VERSION 5.7 ;
BUSBITCHARS "[]" ;
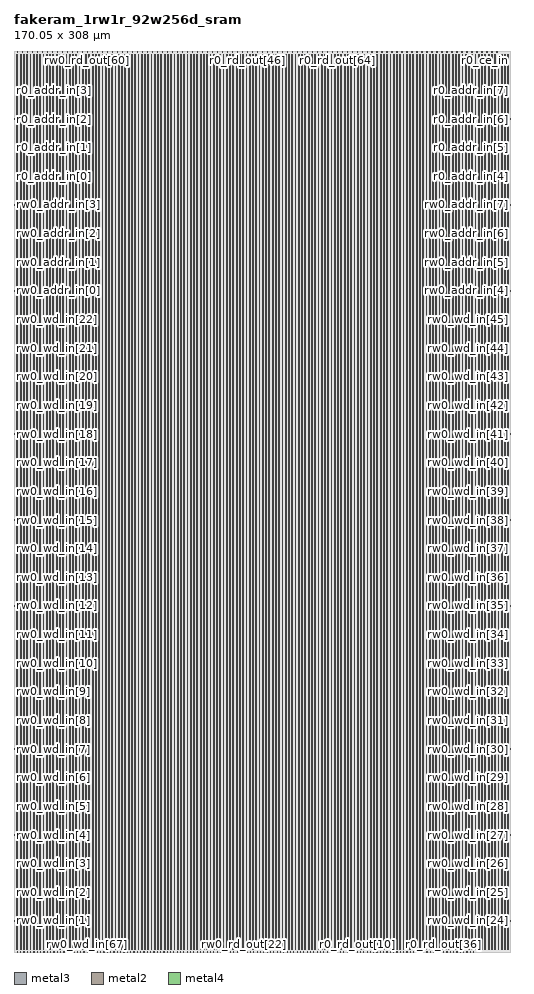
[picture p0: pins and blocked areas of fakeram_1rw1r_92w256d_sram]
MACRO fakeram_1rw1r_92w256d_sram
  FOREIGN fakeram_1rw1r_92w256d_sram 0 0 ;
  SYMMETRY X Y R90 ;
  SIZE 170.050 BY 308.000 ;
  CLASS BLOCK ;
  PIN rw0_wd_in[0]
    DIRECTION INPUT ;
    USE SIGNAL ;
    SHAPE ABUTMENT ;
    PORT
      LAYER metal3 ;
      RECT 0.000 0.805 0.210 0.875 ;
    END
  END rw0_wd_in[0]
  PIN rw0_wd_in[1]
    DIRECTION INPUT ;
    USE SIGNAL ;
    SHAPE ABUTMENT ;
    PORT
      LAYER metal3 ;
      RECT 0.000 10.605 0.210 10.675 ;
    END
  END rw0_wd_in[1]
  PIN rw0_wd_in[2]
    DIRECTION INPUT ;
    USE SIGNAL ;
    SHAPE ABUTMENT ;
    PORT
      LAYER metal3 ;
      RECT 0.000 20.405 0.210 20.475 ;
    END
  END rw0_wd_in[2]
  PIN rw0_wd_in[3]
    DIRECTION INPUT ;
    USE SIGNAL ;
    SHAPE ABUTMENT ;
    PORT
      LAYER metal3 ;
      RECT 0.000 30.205 0.210 30.275 ;
    END
  END rw0_wd_in[3]
  PIN rw0_wd_in[4]
    DIRECTION INPUT ;
    USE SIGNAL ;
    SHAPE ABUTMENT ;
    PORT
      LAYER metal3 ;
      RECT 0.000 40.005 0.210 40.075 ;
    END
  END rw0_wd_in[4]
  PIN rw0_wd_in[5]
    DIRECTION INPUT ;
    USE SIGNAL ;
    SHAPE ABUTMENT ;
    PORT
      LAYER metal3 ;
      RECT 0.000 49.805 0.210 49.875 ;
    END
  END rw0_wd_in[5]
  PIN rw0_wd_in[6]
    DIRECTION INPUT ;
    USE SIGNAL ;
    SHAPE ABUTMENT ;
    PORT
      LAYER metal3 ;
      RECT 0.000 59.605 0.210 59.675 ;
    END
  END rw0_wd_in[6]
  PIN rw0_wd_in[7]
    DIRECTION INPUT ;
    USE SIGNAL ;
    SHAPE ABUTMENT ;
    PORT
      LAYER metal3 ;
      RECT 0.000 69.405 0.210 69.475 ;
    END
  END rw0_wd_in[7]
  PIN rw0_wd_in[8]
    DIRECTION INPUT ;
    USE SIGNAL ;
    SHAPE ABUTMENT ;
    PORT
      LAYER metal3 ;
      RECT 0.000 79.205 0.210 79.275 ;
    END
  END rw0_wd_in[8]
  PIN rw0_wd_in[9]
    DIRECTION INPUT ;
    USE SIGNAL ;
    SHAPE ABUTMENT ;
    PORT
      LAYER metal3 ;
      RECT 0.000 89.005 0.210 89.075 ;
    END
  END rw0_wd_in[9]
  PIN rw0_wd_in[10]
    DIRECTION INPUT ;
    USE SIGNAL ;
    SHAPE ABUTMENT ;
    PORT
      LAYER metal3 ;
      RECT 0.000 98.805 0.210 98.875 ;
    END
  END rw0_wd_in[10]
  PIN rw0_wd_in[11]
    DIRECTION INPUT ;
    USE SIGNAL ;
    SHAPE ABUTMENT ;
    PORT
      LAYER metal3 ;
      RECT 0.000 108.605 0.210 108.675 ;
    END
  END rw0_wd_in[11]
  PIN rw0_wd_in[12]
    DIRECTION INPUT ;
    USE SIGNAL ;
    SHAPE ABUTMENT ;
    PORT
      LAYER metal3 ;
      RECT 0.000 118.405 0.210 118.475 ;
    END
  END rw0_wd_in[12]
  PIN rw0_wd_in[13]
    DIRECTION INPUT ;
    USE SIGNAL ;
    SHAPE ABUTMENT ;
    PORT
      LAYER metal3 ;
      RECT 0.000 128.205 0.210 128.275 ;
    END
  END rw0_wd_in[13]
  PIN rw0_wd_in[14]
    DIRECTION INPUT ;
    USE SIGNAL ;
    SHAPE ABUTMENT ;
    PORT
      LAYER metal3 ;
      RECT 0.000 138.005 0.210 138.075 ;
    END
  END rw0_wd_in[14]
  PIN rw0_wd_in[15]
    DIRECTION INPUT ;
    USE SIGNAL ;
    SHAPE ABUTMENT ;
    PORT
      LAYER metal3 ;
      RECT 0.000 147.805 0.210 147.875 ;
    END
  END rw0_wd_in[15]
  PIN rw0_wd_in[16]
    DIRECTION INPUT ;
    USE SIGNAL ;
    SHAPE ABUTMENT ;
    PORT
      LAYER metal3 ;
      RECT 0.000 157.605 0.210 157.675 ;
    END
  END rw0_wd_in[16]
  PIN rw0_wd_in[17]
    DIRECTION INPUT ;
    USE SIGNAL ;
    SHAPE ABUTMENT ;
    PORT
      LAYER metal3 ;
      RECT 0.000 167.405 0.210 167.475 ;
    END
  END rw0_wd_in[17]
  PIN rw0_wd_in[18]
    DIRECTION INPUT ;
    USE SIGNAL ;
    SHAPE ABUTMENT ;
    PORT
      LAYER metal3 ;
      RECT 0.000 177.205 0.210 177.275 ;
    END
  END rw0_wd_in[18]
  PIN rw0_wd_in[19]
    DIRECTION INPUT ;
    USE SIGNAL ;
    SHAPE ABUTMENT ;
    PORT
      LAYER metal3 ;
      RECT 0.000 187.005 0.210 187.075 ;
    END
  END rw0_wd_in[19]
  PIN rw0_wd_in[20]
    DIRECTION INPUT ;
    USE SIGNAL ;
    SHAPE ABUTMENT ;
    PORT
      LAYER metal3 ;
      RECT 0.000 196.805 0.210 196.875 ;
    END
  END rw0_wd_in[20]
  PIN rw0_wd_in[21]
    DIRECTION INPUT ;
    USE SIGNAL ;
    SHAPE ABUTMENT ;
    PORT
      LAYER metal3 ;
      RECT 0.000 206.605 0.210 206.675 ;
    END
  END rw0_wd_in[21]
  PIN rw0_wd_in[22]
    DIRECTION INPUT ;
    USE SIGNAL ;
    SHAPE ABUTMENT ;
    PORT
      LAYER metal3 ;
      RECT 0.000 216.405 0.210 216.475 ;
    END
  END rw0_wd_in[22]
  PIN rw0_wd_in[23]
    DIRECTION INPUT ;
    USE SIGNAL ;
    SHAPE ABUTMENT ;
    PORT
      LAYER metal3 ;
      RECT 169.840 0.805 170.050 0.875 ;
    END
  END rw0_wd_in[23]
  PIN rw0_wd_in[24]
    DIRECTION INPUT ;
    USE SIGNAL ;
    SHAPE ABUTMENT ;
    PORT
      LAYER metal3 ;
      RECT 169.840 10.605 170.050 10.675 ;
    END
  END rw0_wd_in[24]
  PIN rw0_wd_in[25]
    DIRECTION INPUT ;
    USE SIGNAL ;
    SHAPE ABUTMENT ;
    PORT
      LAYER metal3 ;
      RECT 169.840 20.405 170.050 20.475 ;
    END
  END rw0_wd_in[25]
  PIN rw0_wd_in[26]
    DIRECTION INPUT ;
    USE SIGNAL ;
    SHAPE ABUTMENT ;
    PORT
      LAYER metal3 ;
      RECT 169.840 30.205 170.050 30.275 ;
    END
  END rw0_wd_in[26]
  PIN rw0_wd_in[27]
    DIRECTION INPUT ;
    USE SIGNAL ;
    SHAPE ABUTMENT ;
    PORT
      LAYER metal3 ;
      RECT 169.840 40.005 170.050 40.075 ;
    END
  END rw0_wd_in[27]
  PIN rw0_wd_in[28]
    DIRECTION INPUT ;
    USE SIGNAL ;
    SHAPE ABUTMENT ;
    PORT
      LAYER metal3 ;
      RECT 169.840 49.805 170.050 49.875 ;
    END
  END rw0_wd_in[28]
  PIN rw0_wd_in[29]
    DIRECTION INPUT ;
    USE SIGNAL ;
    SHAPE ABUTMENT ;
    PORT
      LAYER metal3 ;
      RECT 169.840 59.605 170.050 59.675 ;
    END
  END rw0_wd_in[29]
  PIN rw0_wd_in[30]
    DIRECTION INPUT ;
    USE SIGNAL ;
    SHAPE ABUTMENT ;
    PORT
      LAYER metal3 ;
      RECT 169.840 69.405 170.050 69.475 ;
    END
  END rw0_wd_in[30]
  PIN rw0_wd_in[31]
    DIRECTION INPUT ;
    USE SIGNAL ;
    SHAPE ABUTMENT ;
    PORT
      LAYER metal3 ;
      RECT 169.840 79.205 170.050 79.275 ;
    END
  END rw0_wd_in[31]
  PIN rw0_wd_in[32]
    DIRECTION INPUT ;
    USE SIGNAL ;
    SHAPE ABUTMENT ;
    PORT
      LAYER metal3 ;
      RECT 169.840 89.005 170.050 89.075 ;
    END
  END rw0_wd_in[32]
  PIN rw0_wd_in[33]
    DIRECTION INPUT ;
    USE SIGNAL ;
    SHAPE ABUTMENT ;
    PORT
      LAYER metal3 ;
      RECT 169.840 98.805 170.050 98.875 ;
    END
  END rw0_wd_in[33]
  PIN rw0_wd_in[34]
    DIRECTION INPUT ;
    USE SIGNAL ;
    SHAPE ABUTMENT ;
    PORT
      LAYER metal3 ;
      RECT 169.840 108.605 170.050 108.675 ;
    END
  END rw0_wd_in[34]
  PIN rw0_wd_in[35]
    DIRECTION INPUT ;
    USE SIGNAL ;
    SHAPE ABUTMENT ;
    PORT
      LAYER metal3 ;
      RECT 169.840 118.405 170.050 118.475 ;
    END
  END rw0_wd_in[35]
  PIN rw0_wd_in[36]
    DIRECTION INPUT ;
    USE SIGNAL ;
    SHAPE ABUTMENT ;
    PORT
      LAYER metal3 ;
      RECT 169.840 128.205 170.050 128.275 ;
    END
  END rw0_wd_in[36]
  PIN rw0_wd_in[37]
    DIRECTION INPUT ;
    USE SIGNAL ;
    SHAPE ABUTMENT ;
    PORT
      LAYER metal3 ;
      RECT 169.840 138.005 170.050 138.075 ;
    END
  END rw0_wd_in[37]
  PIN rw0_wd_in[38]
    DIRECTION INPUT ;
    USE SIGNAL ;
    SHAPE ABUTMENT ;
    PORT
      LAYER metal3 ;
      RECT 169.840 147.805 170.050 147.875 ;
    END
  END rw0_wd_in[38]
  PIN rw0_wd_in[39]
    DIRECTION INPUT ;
    USE SIGNAL ;
    SHAPE ABUTMENT ;
    PORT
      LAYER metal3 ;
      RECT 169.840 157.605 170.050 157.675 ;
    END
  END rw0_wd_in[39]
  PIN rw0_wd_in[40]
    DIRECTION INPUT ;
    USE SIGNAL ;
    SHAPE ABUTMENT ;
    PORT
      LAYER metal3 ;
      RECT 169.840 167.405 170.050 167.475 ;
    END
  END rw0_wd_in[40]
  PIN rw0_wd_in[41]
    DIRECTION INPUT ;
    USE SIGNAL ;
    SHAPE ABUTMENT ;
    PORT
      LAYER metal3 ;
      RECT 169.840 177.205 170.050 177.275 ;
    END
  END rw0_wd_in[41]
  PIN rw0_wd_in[42]
    DIRECTION INPUT ;
    USE SIGNAL ;
    SHAPE ABUTMENT ;
    PORT
      LAYER metal3 ;
      RECT 169.840 187.005 170.050 187.075 ;
    END
  END rw0_wd_in[42]
  PIN rw0_wd_in[43]
    DIRECTION INPUT ;
    USE SIGNAL ;
    SHAPE ABUTMENT ;
    PORT
      LAYER metal3 ;
      RECT 169.840 196.805 170.050 196.875 ;
    END
  END rw0_wd_in[43]
  PIN rw0_wd_in[44]
    DIRECTION INPUT ;
    USE SIGNAL ;
    SHAPE ABUTMENT ;
    PORT
      LAYER metal3 ;
      RECT 169.840 206.605 170.050 206.675 ;
    END
  END rw0_wd_in[44]
  PIN rw0_wd_in[45]
    DIRECTION INPUT ;
    USE SIGNAL ;
    SHAPE ABUTMENT ;
    PORT
      LAYER metal3 ;
      RECT 169.840 216.405 170.050 216.475 ;
    END
  END rw0_wd_in[45]
  PIN rw0_wd_in[46]
    DIRECTION INPUT ;
    USE SIGNAL ;
    SHAPE ABUTMENT ;
    PORT
      LAYER metal2 ;
      RECT 1.105 0.000 1.175 0.210 ;
    END
  END rw0_wd_in[46]
  PIN rw0_wd_in[47]
    DIRECTION INPUT ;
    USE SIGNAL ;
    SHAPE ABUTMENT ;
    PORT
      LAYER metal2 ;
      RECT 2.245 0.000 2.315 0.210 ;
    END
  END rw0_wd_in[47]
  PIN rw0_wd_in[48]
    DIRECTION INPUT ;
    USE SIGNAL ;
    SHAPE ABUTMENT ;
    PORT
      LAYER metal2 ;
      RECT 3.385 0.000 3.455 0.210 ;
    END
  END rw0_wd_in[48]
  PIN rw0_wd_in[49]
    DIRECTION INPUT ;
    USE SIGNAL ;
    SHAPE ABUTMENT ;
    PORT
      LAYER metal2 ;
      RECT 4.525 0.000 4.595 0.210 ;
    END
  END rw0_wd_in[49]
  PIN rw0_wd_in[50]
    DIRECTION INPUT ;
    USE SIGNAL ;
    SHAPE ABUTMENT ;
    PORT
      LAYER metal2 ;
      RECT 5.665 0.000 5.735 0.210 ;
    END
  END rw0_wd_in[50]
  PIN rw0_wd_in[51]
    DIRECTION INPUT ;
    USE SIGNAL ;
    SHAPE ABUTMENT ;
    PORT
      LAYER metal2 ;
      RECT 6.805 0.000 6.875 0.210 ;
    END
  END rw0_wd_in[51]
  PIN rw0_wd_in[52]
    DIRECTION INPUT ;
    USE SIGNAL ;
    SHAPE ABUTMENT ;
    PORT
      LAYER metal2 ;
      RECT 7.945 0.000 8.015 0.210 ;
    END
  END rw0_wd_in[52]
  PIN rw0_wd_in[53]
    DIRECTION INPUT ;
    USE SIGNAL ;
    SHAPE ABUTMENT ;
    PORT
      LAYER metal2 ;
      RECT 9.085 0.000 9.155 0.210 ;
    END
  END rw0_wd_in[53]
  PIN rw0_wd_in[54]
    DIRECTION INPUT ;
    USE SIGNAL ;
    SHAPE ABUTMENT ;
    PORT
      LAYER metal2 ;
      RECT 10.225 0.000 10.295 0.210 ;
    END
  END rw0_wd_in[54]
  PIN rw0_wd_in[55]
    DIRECTION INPUT ;
    USE SIGNAL ;
    SHAPE ABUTMENT ;
    PORT
      LAYER metal2 ;
      RECT 11.365 0.000 11.435 0.210 ;
    END
  END rw0_wd_in[55]
  PIN rw0_wd_in[56]
    DIRECTION INPUT ;
    USE SIGNAL ;
    SHAPE ABUTMENT ;
    PORT
      LAYER metal2 ;
      RECT 12.505 0.000 12.575 0.210 ;
    END
  END rw0_wd_in[56]
  PIN rw0_wd_in[57]
    DIRECTION INPUT ;
    USE SIGNAL ;
    SHAPE ABUTMENT ;
    PORT
      LAYER metal2 ;
      RECT 13.645 0.000 13.715 0.210 ;
    END
  END rw0_wd_in[57]
  PIN rw0_wd_in[58]
    DIRECTION INPUT ;
    USE SIGNAL ;
    SHAPE ABUTMENT ;
    PORT
      LAYER metal2 ;
      RECT 14.785 0.000 14.855 0.210 ;
    END
  END rw0_wd_in[58]
  PIN rw0_wd_in[59]
    DIRECTION INPUT ;
    USE SIGNAL ;
    SHAPE ABUTMENT ;
    PORT
      LAYER metal2 ;
      RECT 15.925 0.000 15.995 0.210 ;
    END
  END rw0_wd_in[59]
  PIN rw0_wd_in[60]
    DIRECTION INPUT ;
    USE SIGNAL ;
    SHAPE ABUTMENT ;
    PORT
      LAYER metal2 ;
      RECT 17.065 0.000 17.135 0.210 ;
    END
  END rw0_wd_in[60]
  PIN rw0_wd_in[61]
    DIRECTION INPUT ;
    USE SIGNAL ;
    SHAPE ABUTMENT ;
    PORT
      LAYER metal2 ;
      RECT 18.205 0.000 18.275 0.210 ;
    END
  END rw0_wd_in[61]
  PIN rw0_wd_in[62]
    DIRECTION INPUT ;
    USE SIGNAL ;
    SHAPE ABUTMENT ;
    PORT
      LAYER metal2 ;
      RECT 19.345 0.000 19.415 0.210 ;
    END
  END rw0_wd_in[62]
  PIN rw0_wd_in[63]
    DIRECTION INPUT ;
    USE SIGNAL ;
    SHAPE ABUTMENT ;
    PORT
      LAYER metal2 ;
      RECT 20.485 0.000 20.555 0.210 ;
    END
  END rw0_wd_in[63]
  PIN rw0_wd_in[64]
    DIRECTION INPUT ;
    USE SIGNAL ;
    SHAPE ABUTMENT ;
    PORT
      LAYER metal2 ;
      RECT 21.625 0.000 21.695 0.210 ;
    END
  END rw0_wd_in[64]
  PIN rw0_wd_in[65]
    DIRECTION INPUT ;
    USE SIGNAL ;
    SHAPE ABUTMENT ;
    PORT
      LAYER metal2 ;
      RECT 22.765 0.000 22.835 0.210 ;
    END
  END rw0_wd_in[65]
  PIN rw0_wd_in[66]
    DIRECTION INPUT ;
    USE SIGNAL ;
    SHAPE ABUTMENT ;
    PORT
      LAYER metal2 ;
      RECT 23.905 0.000 23.975 0.210 ;
    END
  END rw0_wd_in[66]
  PIN rw0_wd_in[67]
    DIRECTION INPUT ;
    USE SIGNAL ;
    SHAPE ABUTMENT ;
    PORT
      LAYER metal2 ;
      RECT 25.045 0.000 25.115 0.210 ;
    END
  END rw0_wd_in[67]
  PIN rw0_wd_in[68]
    DIRECTION INPUT ;
    USE SIGNAL ;
    SHAPE ABUTMENT ;
    PORT
      LAYER metal2 ;
      RECT 26.185 0.000 26.255 0.210 ;
    END
  END rw0_wd_in[68]
  PIN rw0_wd_in[69]
    DIRECTION INPUT ;
    USE SIGNAL ;
    SHAPE ABUTMENT ;
    PORT
      LAYER metal2 ;
      RECT 27.325 0.000 27.395 0.210 ;
    END
  END rw0_wd_in[69]
  PIN rw0_wd_in[70]
    DIRECTION INPUT ;
    USE SIGNAL ;
    SHAPE ABUTMENT ;
    PORT
      LAYER metal2 ;
      RECT 28.465 0.000 28.535 0.210 ;
    END
  END rw0_wd_in[70]
  PIN rw0_wd_in[71]
    DIRECTION INPUT ;
    USE SIGNAL ;
    SHAPE ABUTMENT ;
    PORT
      LAYER metal2 ;
      RECT 29.605 0.000 29.675 0.210 ;
    END
  END rw0_wd_in[71]
  PIN rw0_wd_in[72]
    DIRECTION INPUT ;
    USE SIGNAL ;
    SHAPE ABUTMENT ;
    PORT
      LAYER metal2 ;
      RECT 30.745 0.000 30.815 0.210 ;
    END
  END rw0_wd_in[72]
  PIN rw0_wd_in[73]
    DIRECTION INPUT ;
    USE SIGNAL ;
    SHAPE ABUTMENT ;
    PORT
      LAYER metal2 ;
      RECT 31.885 0.000 31.955 0.210 ;
    END
  END rw0_wd_in[73]
  PIN rw0_wd_in[74]
    DIRECTION INPUT ;
    USE SIGNAL ;
    SHAPE ABUTMENT ;
    PORT
      LAYER metal2 ;
      RECT 33.025 0.000 33.095 0.210 ;
    END
  END rw0_wd_in[74]
  PIN rw0_wd_in[75]
    DIRECTION INPUT ;
    USE SIGNAL ;
    SHAPE ABUTMENT ;
    PORT
      LAYER metal2 ;
      RECT 34.165 0.000 34.235 0.210 ;
    END
  END rw0_wd_in[75]
  PIN rw0_wd_in[76]
    DIRECTION INPUT ;
    USE SIGNAL ;
    SHAPE ABUTMENT ;
    PORT
      LAYER metal2 ;
      RECT 35.305 0.000 35.375 0.210 ;
    END
  END rw0_wd_in[76]
  PIN rw0_wd_in[77]
    DIRECTION INPUT ;
    USE SIGNAL ;
    SHAPE ABUTMENT ;
    PORT
      LAYER metal2 ;
      RECT 36.445 0.000 36.515 0.210 ;
    END
  END rw0_wd_in[77]
  PIN rw0_wd_in[78]
    DIRECTION INPUT ;
    USE SIGNAL ;
    SHAPE ABUTMENT ;
    PORT
      LAYER metal2 ;
      RECT 37.585 0.000 37.655 0.210 ;
    END
  END rw0_wd_in[78]
  PIN rw0_wd_in[79]
    DIRECTION INPUT ;
    USE SIGNAL ;
    SHAPE ABUTMENT ;
    PORT
      LAYER metal2 ;
      RECT 38.725 0.000 38.795 0.210 ;
    END
  END rw0_wd_in[79]
  PIN rw0_wd_in[80]
    DIRECTION INPUT ;
    USE SIGNAL ;
    SHAPE ABUTMENT ;
    PORT
      LAYER metal2 ;
      RECT 39.865 0.000 39.935 0.210 ;
    END
  END rw0_wd_in[80]
  PIN rw0_wd_in[81]
    DIRECTION INPUT ;
    USE SIGNAL ;
    SHAPE ABUTMENT ;
    PORT
      LAYER metal2 ;
      RECT 41.005 0.000 41.075 0.210 ;
    END
  END rw0_wd_in[81]
  PIN rw0_wd_in[82]
    DIRECTION INPUT ;
    USE SIGNAL ;
    SHAPE ABUTMENT ;
    PORT
      LAYER metal2 ;
      RECT 42.145 0.000 42.215 0.210 ;
    END
  END rw0_wd_in[82]
  PIN rw0_wd_in[83]
    DIRECTION INPUT ;
    USE SIGNAL ;
    SHAPE ABUTMENT ;
    PORT
      LAYER metal2 ;
      RECT 43.285 0.000 43.355 0.210 ;
    END
  END rw0_wd_in[83]
  PIN rw0_wd_in[84]
    DIRECTION INPUT ;
    USE SIGNAL ;
    SHAPE ABUTMENT ;
    PORT
      LAYER metal2 ;
      RECT 44.425 0.000 44.495 0.210 ;
    END
  END rw0_wd_in[84]
  PIN rw0_wd_in[85]
    DIRECTION INPUT ;
    USE SIGNAL ;
    SHAPE ABUTMENT ;
    PORT
      LAYER metal2 ;
      RECT 45.565 0.000 45.635 0.210 ;
    END
  END rw0_wd_in[85]
  PIN rw0_wd_in[86]
    DIRECTION INPUT ;
    USE SIGNAL ;
    SHAPE ABUTMENT ;
    PORT
      LAYER metal2 ;
      RECT 46.705 0.000 46.775 0.210 ;
    END
  END rw0_wd_in[86]
  PIN rw0_wd_in[87]
    DIRECTION INPUT ;
    USE SIGNAL ;
    SHAPE ABUTMENT ;
    PORT
      LAYER metal2 ;
      RECT 47.845 0.000 47.915 0.210 ;
    END
  END rw0_wd_in[87]
  PIN rw0_wd_in[88]
    DIRECTION INPUT ;
    USE SIGNAL ;
    SHAPE ABUTMENT ;
    PORT
      LAYER metal2 ;
      RECT 48.985 0.000 49.055 0.210 ;
    END
  END rw0_wd_in[88]
  PIN rw0_wd_in[89]
    DIRECTION INPUT ;
    USE SIGNAL ;
    SHAPE ABUTMENT ;
    PORT
      LAYER metal2 ;
      RECT 50.125 0.000 50.195 0.210 ;
    END
  END rw0_wd_in[89]
  PIN rw0_wd_in[90]
    DIRECTION INPUT ;
    USE SIGNAL ;
    SHAPE ABUTMENT ;
    PORT
      LAYER metal2 ;
      RECT 51.265 0.000 51.335 0.210 ;
    END
  END rw0_wd_in[90]
  PIN rw0_wd_in[91]
    DIRECTION INPUT ;
    USE SIGNAL ;
    SHAPE ABUTMENT ;
    PORT
      LAYER metal2 ;
      RECT 52.405 0.000 52.475 0.210 ;
    END
  END rw0_wd_in[91]
  PIN rw0_rd_out[0]
    DIRECTION OUTPUT ;
    USE SIGNAL ;
    SHAPE ABUTMENT ;
    PORT
      LAYER metal2 ;
      RECT 53.545 0.000 53.615 0.210 ;
    END
  END rw0_rd_out[0]
  PIN rw0_rd_out[1]
    DIRECTION OUTPUT ;
    USE SIGNAL ;
    SHAPE ABUTMENT ;
    PORT
      LAYER metal2 ;
      RECT 54.685 0.000 54.755 0.210 ;
    END
  END rw0_rd_out[1]
  PIN rw0_rd_out[2]
    DIRECTION OUTPUT ;
    USE SIGNAL ;
    SHAPE ABUTMENT ;
    PORT
      LAYER metal2 ;
      RECT 55.825 0.000 55.895 0.210 ;
    END
  END rw0_rd_out[2]
  PIN rw0_rd_out[3]
    DIRECTION OUTPUT ;
    USE SIGNAL ;
    SHAPE ABUTMENT ;
    PORT
      LAYER metal2 ;
      RECT 56.965 0.000 57.035 0.210 ;
    END
  END rw0_rd_out[3]
  PIN rw0_rd_out[4]
    DIRECTION OUTPUT ;
    USE SIGNAL ;
    SHAPE ABUTMENT ;
    PORT
      LAYER metal2 ;
      RECT 58.105 0.000 58.175 0.210 ;
    END
  END rw0_rd_out[4]
  PIN rw0_rd_out[5]
    DIRECTION OUTPUT ;
    USE SIGNAL ;
    SHAPE ABUTMENT ;
    PORT
      LAYER metal2 ;
      RECT 59.245 0.000 59.315 0.210 ;
    END
  END rw0_rd_out[5]
  PIN rw0_rd_out[6]
    DIRECTION OUTPUT ;
    USE SIGNAL ;
    SHAPE ABUTMENT ;
    PORT
      LAYER metal2 ;
      RECT 60.385 0.000 60.455 0.210 ;
    END
  END rw0_rd_out[6]
  PIN rw0_rd_out[7]
    DIRECTION OUTPUT ;
    USE SIGNAL ;
    SHAPE ABUTMENT ;
    PORT
      LAYER metal2 ;
      RECT 61.525 0.000 61.595 0.210 ;
    END
  END rw0_rd_out[7]
  PIN rw0_rd_out[8]
    DIRECTION OUTPUT ;
    USE SIGNAL ;
    SHAPE ABUTMENT ;
    PORT
      LAYER metal2 ;
      RECT 62.665 0.000 62.735 0.210 ;
    END
  END rw0_rd_out[8]
  PIN rw0_rd_out[9]
    DIRECTION OUTPUT ;
    USE SIGNAL ;
    SHAPE ABUTMENT ;
    PORT
      LAYER metal2 ;
      RECT 63.805 0.000 63.875 0.210 ;
    END
  END rw0_rd_out[9]
  PIN rw0_rd_out[10]
    DIRECTION OUTPUT ;
    USE SIGNAL ;
    SHAPE ABUTMENT ;
    PORT
      LAYER metal2 ;
      RECT 64.945 0.000 65.015 0.210 ;
    END
  END rw0_rd_out[10]
  PIN rw0_rd_out[11]
    DIRECTION OUTPUT ;
    USE SIGNAL ;
    SHAPE ABUTMENT ;
    PORT
      LAYER metal2 ;
      RECT 66.085 0.000 66.155 0.210 ;
    END
  END rw0_rd_out[11]
  PIN rw0_rd_out[12]
    DIRECTION OUTPUT ;
    USE SIGNAL ;
    SHAPE ABUTMENT ;
    PORT
      LAYER metal2 ;
      RECT 67.225 0.000 67.295 0.210 ;
    END
  END rw0_rd_out[12]
  PIN rw0_rd_out[13]
    DIRECTION OUTPUT ;
    USE SIGNAL ;
    SHAPE ABUTMENT ;
    PORT
      LAYER metal2 ;
      RECT 68.365 0.000 68.435 0.210 ;
    END
  END rw0_rd_out[13]
  PIN rw0_rd_out[14]
    DIRECTION OUTPUT ;
    USE SIGNAL ;
    SHAPE ABUTMENT ;
    PORT
      LAYER metal2 ;
      RECT 69.505 0.000 69.575 0.210 ;
    END
  END rw0_rd_out[14]
  PIN rw0_rd_out[15]
    DIRECTION OUTPUT ;
    USE SIGNAL ;
    SHAPE ABUTMENT ;
    PORT
      LAYER metal2 ;
      RECT 70.645 0.000 70.715 0.210 ;
    END
  END rw0_rd_out[15]
  PIN rw0_rd_out[16]
    DIRECTION OUTPUT ;
    USE SIGNAL ;
    SHAPE ABUTMENT ;
    PORT
      LAYER metal2 ;
      RECT 71.785 0.000 71.855 0.210 ;
    END
  END rw0_rd_out[16]
  PIN rw0_rd_out[17]
    DIRECTION OUTPUT ;
    USE SIGNAL ;
    SHAPE ABUTMENT ;
    PORT
      LAYER metal2 ;
      RECT 72.925 0.000 72.995 0.210 ;
    END
  END rw0_rd_out[17]
  PIN rw0_rd_out[18]
    DIRECTION OUTPUT ;
    USE SIGNAL ;
    SHAPE ABUTMENT ;
    PORT
      LAYER metal2 ;
      RECT 74.065 0.000 74.135 0.210 ;
    END
  END rw0_rd_out[18]
  PIN rw0_rd_out[19]
    DIRECTION OUTPUT ;
    USE SIGNAL ;
    SHAPE ABUTMENT ;
    PORT
      LAYER metal2 ;
      RECT 75.205 0.000 75.275 0.210 ;
    END
  END rw0_rd_out[19]
  PIN rw0_rd_out[20]
    DIRECTION OUTPUT ;
    USE SIGNAL ;
    SHAPE ABUTMENT ;
    PORT
      LAYER metal2 ;
      RECT 76.345 0.000 76.415 0.210 ;
    END
  END rw0_rd_out[20]
  PIN rw0_rd_out[21]
    DIRECTION OUTPUT ;
    USE SIGNAL ;
    SHAPE ABUTMENT ;
    PORT
      LAYER metal2 ;
      RECT 77.485 0.000 77.555 0.210 ;
    END
  END rw0_rd_out[21]
  PIN rw0_rd_out[22]
    DIRECTION OUTPUT ;
    USE SIGNAL ;
    SHAPE ABUTMENT ;
    PORT
      LAYER metal2 ;
      RECT 78.625 0.000 78.695 0.210 ;
    END
  END rw0_rd_out[22]
  PIN rw0_rd_out[23]
    DIRECTION OUTPUT ;
    USE SIGNAL ;
    SHAPE ABUTMENT ;
    PORT
      LAYER metal2 ;
      RECT 79.765 0.000 79.835 0.210 ;
    END
  END rw0_rd_out[23]
  PIN rw0_rd_out[24]
    DIRECTION OUTPUT ;
    USE SIGNAL ;
    SHAPE ABUTMENT ;
    PORT
      LAYER metal2 ;
      RECT 80.905 0.000 80.975 0.210 ;
    END
  END rw0_rd_out[24]
  PIN rw0_rd_out[25]
    DIRECTION OUTPUT ;
    USE SIGNAL ;
    SHAPE ABUTMENT ;
    PORT
      LAYER metal2 ;
      RECT 82.045 0.000 82.115 0.210 ;
    END
  END rw0_rd_out[25]
  PIN rw0_rd_out[26]
    DIRECTION OUTPUT ;
    USE SIGNAL ;
    SHAPE ABUTMENT ;
    PORT
      LAYER metal2 ;
      RECT 83.185 0.000 83.255 0.210 ;
    END
  END rw0_rd_out[26]
  PIN rw0_rd_out[27]
    DIRECTION OUTPUT ;
    USE SIGNAL ;
    SHAPE ABUTMENT ;
    PORT
      LAYER metal2 ;
      RECT 84.325 0.000 84.395 0.210 ;
    END
  END rw0_rd_out[27]
  PIN rw0_rd_out[28]
    DIRECTION OUTPUT ;
    USE SIGNAL ;
    SHAPE ABUTMENT ;
    PORT
      LAYER metal2 ;
      RECT 85.465 0.000 85.535 0.210 ;
    END
  END rw0_rd_out[28]
  PIN rw0_rd_out[29]
    DIRECTION OUTPUT ;
    USE SIGNAL ;
    SHAPE ABUTMENT ;
    PORT
      LAYER metal2 ;
      RECT 86.605 0.000 86.675 0.210 ;
    END
  END rw0_rd_out[29]
  PIN rw0_rd_out[30]
    DIRECTION OUTPUT ;
    USE SIGNAL ;
    SHAPE ABUTMENT ;
    PORT
      LAYER metal2 ;
      RECT 87.745 0.000 87.815 0.210 ;
    END
  END rw0_rd_out[30]
  PIN rw0_rd_out[31]
    DIRECTION OUTPUT ;
    USE SIGNAL ;
    SHAPE ABUTMENT ;
    PORT
      LAYER metal2 ;
      RECT 88.885 0.000 88.955 0.210 ;
    END
  END rw0_rd_out[31]
  PIN rw0_rd_out[32]
    DIRECTION OUTPUT ;
    USE SIGNAL ;
    SHAPE ABUTMENT ;
    PORT
      LAYER metal2 ;
      RECT 90.025 0.000 90.095 0.210 ;
    END
  END rw0_rd_out[32]
  PIN rw0_rd_out[33]
    DIRECTION OUTPUT ;
    USE SIGNAL ;
    SHAPE ABUTMENT ;
    PORT
      LAYER metal2 ;
      RECT 91.165 0.000 91.235 0.210 ;
    END
  END rw0_rd_out[33]
  PIN rw0_rd_out[34]
    DIRECTION OUTPUT ;
    USE SIGNAL ;
    SHAPE ABUTMENT ;
    PORT
      LAYER metal2 ;
      RECT 92.305 0.000 92.375 0.210 ;
    END
  END rw0_rd_out[34]
  PIN rw0_rd_out[35]
    DIRECTION OUTPUT ;
    USE SIGNAL ;
    SHAPE ABUTMENT ;
    PORT
      LAYER metal2 ;
      RECT 93.445 0.000 93.515 0.210 ;
    END
  END rw0_rd_out[35]
  PIN rw0_rd_out[36]
    DIRECTION OUTPUT ;
    USE SIGNAL ;
    SHAPE ABUTMENT ;
    PORT
      LAYER metal2 ;
      RECT 94.585 0.000 94.655 0.210 ;
    END
  END rw0_rd_out[36]
  PIN rw0_rd_out[37]
    DIRECTION OUTPUT ;
    USE SIGNAL ;
    SHAPE ABUTMENT ;
    PORT
      LAYER metal2 ;
      RECT 95.725 0.000 95.795 0.210 ;
    END
  END rw0_rd_out[37]
  PIN rw0_rd_out[38]
    DIRECTION OUTPUT ;
    USE SIGNAL ;
    SHAPE ABUTMENT ;
    PORT
      LAYER metal2 ;
      RECT 96.865 0.000 96.935 0.210 ;
    END
  END rw0_rd_out[38]
  PIN rw0_rd_out[39]
    DIRECTION OUTPUT ;
    USE SIGNAL ;
    SHAPE ABUTMENT ;
    PORT
      LAYER metal2 ;
      RECT 98.005 0.000 98.075 0.210 ;
    END
  END rw0_rd_out[39]
  PIN rw0_rd_out[40]
    DIRECTION OUTPUT ;
    USE SIGNAL ;
    SHAPE ABUTMENT ;
    PORT
      LAYER metal2 ;
      RECT 99.145 0.000 99.215 0.210 ;
    END
  END rw0_rd_out[40]
  PIN rw0_rd_out[41]
    DIRECTION OUTPUT ;
    USE SIGNAL ;
    SHAPE ABUTMENT ;
    PORT
      LAYER metal2 ;
      RECT 100.285 0.000 100.355 0.210 ;
    END
  END rw0_rd_out[41]
  PIN rw0_rd_out[42]
    DIRECTION OUTPUT ;
    USE SIGNAL ;
    SHAPE ABUTMENT ;
    PORT
      LAYER metal2 ;
      RECT 101.425 0.000 101.495 0.210 ;
    END
  END rw0_rd_out[42]
  PIN rw0_rd_out[43]
    DIRECTION OUTPUT ;
    USE SIGNAL ;
    SHAPE ABUTMENT ;
    PORT
      LAYER metal2 ;
      RECT 102.565 0.000 102.635 0.210 ;
    END
  END rw0_rd_out[43]
  PIN rw0_rd_out[44]
    DIRECTION OUTPUT ;
    USE SIGNAL ;
    SHAPE ABUTMENT ;
    PORT
      LAYER metal2 ;
      RECT 103.705 0.000 103.775 0.210 ;
    END
  END rw0_rd_out[44]
  PIN rw0_rd_out[45]
    DIRECTION OUTPUT ;
    USE SIGNAL ;
    SHAPE ABUTMENT ;
    PORT
      LAYER metal2 ;
      RECT 104.845 0.000 104.915 0.210 ;
    END
  END rw0_rd_out[45]
  PIN rw0_rd_out[46]
    DIRECTION OUTPUT ;
    USE SIGNAL ;
    SHAPE ABUTMENT ;
    PORT
      LAYER metal2 ;
      RECT 1.105 307.790 1.175 308.000 ;
    END
  END rw0_rd_out[46]
  PIN rw0_rd_out[47]
    DIRECTION OUTPUT ;
    USE SIGNAL ;
    SHAPE ABUTMENT ;
    PORT
      LAYER metal2 ;
      RECT 2.815 307.790 2.885 308.000 ;
    END
  END rw0_rd_out[47]
  PIN rw0_rd_out[48]
    DIRECTION OUTPUT ;
    USE SIGNAL ;
    SHAPE ABUTMENT ;
    PORT
      LAYER metal2 ;
      RECT 4.525 307.790 4.595 308.000 ;
    END
  END rw0_rd_out[48]
  PIN rw0_rd_out[49]
    DIRECTION OUTPUT ;
    USE SIGNAL ;
    SHAPE ABUTMENT ;
    PORT
      LAYER metal2 ;
      RECT 6.235 307.790 6.305 308.000 ;
    END
  END rw0_rd_out[49]
  PIN rw0_rd_out[50]
    DIRECTION OUTPUT ;
    USE SIGNAL ;
    SHAPE ABUTMENT ;
    PORT
      LAYER metal2 ;
      RECT 7.945 307.790 8.015 308.000 ;
    END
  END rw0_rd_out[50]
  PIN rw0_rd_out[51]
    DIRECTION OUTPUT ;
    USE SIGNAL ;
    SHAPE ABUTMENT ;
    PORT
      LAYER metal2 ;
      RECT 9.655 307.790 9.725 308.000 ;
    END
  END rw0_rd_out[51]
  PIN rw0_rd_out[52]
    DIRECTION OUTPUT ;
    USE SIGNAL ;
    SHAPE ABUTMENT ;
    PORT
      LAYER metal2 ;
      RECT 11.365 307.790 11.435 308.000 ;
    END
  END rw0_rd_out[52]
  PIN rw0_rd_out[53]
    DIRECTION OUTPUT ;
    USE SIGNAL ;
    SHAPE ABUTMENT ;
    PORT
      LAYER metal2 ;
      RECT 13.075 307.790 13.145 308.000 ;
    END
  END rw0_rd_out[53]
  PIN rw0_rd_out[54]
    DIRECTION OUTPUT ;
    USE SIGNAL ;
    SHAPE ABUTMENT ;
    PORT
      LAYER metal2 ;
      RECT 14.785 307.790 14.855 308.000 ;
    END
  END rw0_rd_out[54]
  PIN rw0_rd_out[55]
    DIRECTION OUTPUT ;
    USE SIGNAL ;
    SHAPE ABUTMENT ;
    PORT
      LAYER metal2 ;
      RECT 16.495 307.790 16.565 308.000 ;
    END
  END rw0_rd_out[55]
  PIN rw0_rd_out[56]
    DIRECTION OUTPUT ;
    USE SIGNAL ;
    SHAPE ABUTMENT ;
    PORT
      LAYER metal2 ;
      RECT 18.205 307.790 18.275 308.000 ;
    END
  END rw0_rd_out[56]
  PIN rw0_rd_out[57]
    DIRECTION OUTPUT ;
    USE SIGNAL ;
    SHAPE ABUTMENT ;
    PORT
      LAYER metal2 ;
      RECT 19.915 307.790 19.985 308.000 ;
    END
  END rw0_rd_out[57]
  PIN rw0_rd_out[58]
    DIRECTION OUTPUT ;
    USE SIGNAL ;
    SHAPE ABUTMENT ;
    PORT
      LAYER metal2 ;
      RECT 21.625 307.790 21.695 308.000 ;
    END
  END rw0_rd_out[58]
  PIN rw0_rd_out[59]
    DIRECTION OUTPUT ;
    USE SIGNAL ;
    SHAPE ABUTMENT ;
    PORT
      LAYER metal2 ;
      RECT 23.335 307.790 23.405 308.000 ;
    END
  END rw0_rd_out[59]
  PIN rw0_rd_out[60]
    DIRECTION OUTPUT ;
    USE SIGNAL ;
    SHAPE ABUTMENT ;
    PORT
      LAYER metal2 ;
      RECT 25.045 307.790 25.115 308.000 ;
    END
  END rw0_rd_out[60]
  PIN rw0_rd_out[61]
    DIRECTION OUTPUT ;
    USE SIGNAL ;
    SHAPE ABUTMENT ;
    PORT
      LAYER metal2 ;
      RECT 26.755 307.790 26.825 308.000 ;
    END
  END rw0_rd_out[61]
  PIN rw0_rd_out[62]
    DIRECTION OUTPUT ;
    USE SIGNAL ;
    SHAPE ABUTMENT ;
    PORT
      LAYER metal2 ;
      RECT 28.465 307.790 28.535 308.000 ;
    END
  END rw0_rd_out[62]
  PIN rw0_rd_out[63]
    DIRECTION OUTPUT ;
    USE SIGNAL ;
    SHAPE ABUTMENT ;
    PORT
      LAYER metal2 ;
      RECT 30.175 307.790 30.245 308.000 ;
    END
  END rw0_rd_out[63]
  PIN rw0_rd_out[64]
    DIRECTION OUTPUT ;
    USE SIGNAL ;
    SHAPE ABUTMENT ;
    PORT
      LAYER metal2 ;
      RECT 31.885 307.790 31.955 308.000 ;
    END
  END rw0_rd_out[64]
  PIN rw0_rd_out[65]
    DIRECTION OUTPUT ;
    USE SIGNAL ;
    SHAPE ABUTMENT ;
    PORT
      LAYER metal2 ;
      RECT 33.595 307.790 33.665 308.000 ;
    END
  END rw0_rd_out[65]
  PIN rw0_rd_out[66]
    DIRECTION OUTPUT ;
    USE SIGNAL ;
    SHAPE ABUTMENT ;
    PORT
      LAYER metal2 ;
      RECT 35.305 307.790 35.375 308.000 ;
    END
  END rw0_rd_out[66]
  PIN rw0_rd_out[67]
    DIRECTION OUTPUT ;
    USE SIGNAL ;
    SHAPE ABUTMENT ;
    PORT
      LAYER metal2 ;
      RECT 37.015 307.790 37.085 308.000 ;
    END
  END rw0_rd_out[67]
  PIN rw0_rd_out[68]
    DIRECTION OUTPUT ;
    USE SIGNAL ;
    SHAPE ABUTMENT ;
    PORT
      LAYER metal2 ;
      RECT 38.725 307.790 38.795 308.000 ;
    END
  END rw0_rd_out[68]
  PIN rw0_rd_out[69]
    DIRECTION OUTPUT ;
    USE SIGNAL ;
    SHAPE ABUTMENT ;
    PORT
      LAYER metal2 ;
      RECT 40.435 307.790 40.505 308.000 ;
    END
  END rw0_rd_out[69]
  PIN rw0_rd_out[70]
    DIRECTION OUTPUT ;
    USE SIGNAL ;
    SHAPE ABUTMENT ;
    PORT
      LAYER metal2 ;
      RECT 42.145 307.790 42.215 308.000 ;
    END
  END rw0_rd_out[70]
  PIN rw0_rd_out[71]
    DIRECTION OUTPUT ;
    USE SIGNAL ;
    SHAPE ABUTMENT ;
    PORT
      LAYER metal2 ;
      RECT 43.855 307.790 43.925 308.000 ;
    END
  END rw0_rd_out[71]
  PIN rw0_rd_out[72]
    DIRECTION OUTPUT ;
    USE SIGNAL ;
    SHAPE ABUTMENT ;
    PORT
      LAYER metal2 ;
      RECT 45.565 307.790 45.635 308.000 ;
    END
  END rw0_rd_out[72]
  PIN rw0_rd_out[73]
    DIRECTION OUTPUT ;
    USE SIGNAL ;
    SHAPE ABUTMENT ;
    PORT
      LAYER metal2 ;
      RECT 47.275 307.790 47.345 308.000 ;
    END
  END rw0_rd_out[73]
  PIN rw0_rd_out[74]
    DIRECTION OUTPUT ;
    USE SIGNAL ;
    SHAPE ABUTMENT ;
    PORT
      LAYER metal2 ;
      RECT 48.985 307.790 49.055 308.000 ;
    END
  END rw0_rd_out[74]
  PIN rw0_rd_out[75]
    DIRECTION OUTPUT ;
    USE SIGNAL ;
    SHAPE ABUTMENT ;
    PORT
      LAYER metal2 ;
      RECT 50.695 307.790 50.765 308.000 ;
    END
  END rw0_rd_out[75]
  PIN rw0_rd_out[76]
    DIRECTION OUTPUT ;
    USE SIGNAL ;
    SHAPE ABUTMENT ;
    PORT
      LAYER metal2 ;
      RECT 52.405 307.790 52.475 308.000 ;
    END
  END rw0_rd_out[76]
  PIN rw0_rd_out[77]
    DIRECTION OUTPUT ;
    USE SIGNAL ;
    SHAPE ABUTMENT ;
    PORT
      LAYER metal2 ;
      RECT 54.115 307.790 54.185 308.000 ;
    END
  END rw0_rd_out[77]
  PIN rw0_rd_out[78]
    DIRECTION OUTPUT ;
    USE SIGNAL ;
    SHAPE ABUTMENT ;
    PORT
      LAYER metal2 ;
      RECT 55.825 307.790 55.895 308.000 ;
    END
  END rw0_rd_out[78]
  PIN rw0_rd_out[79]
    DIRECTION OUTPUT ;
    USE SIGNAL ;
    SHAPE ABUTMENT ;
    PORT
      LAYER metal2 ;
      RECT 57.535 307.790 57.605 308.000 ;
    END
  END rw0_rd_out[79]
  PIN rw0_rd_out[80]
    DIRECTION OUTPUT ;
    USE SIGNAL ;
    SHAPE ABUTMENT ;
    PORT
      LAYER metal2 ;
      RECT 59.245 307.790 59.315 308.000 ;
    END
  END rw0_rd_out[80]
  PIN rw0_rd_out[81]
    DIRECTION OUTPUT ;
    USE SIGNAL ;
    SHAPE ABUTMENT ;
    PORT
      LAYER metal2 ;
      RECT 60.955 307.790 61.025 308.000 ;
    END
  END rw0_rd_out[81]
  PIN rw0_rd_out[82]
    DIRECTION OUTPUT ;
    USE SIGNAL ;
    SHAPE ABUTMENT ;
    PORT
      LAYER metal2 ;
      RECT 62.665 307.790 62.735 308.000 ;
    END
  END rw0_rd_out[82]
  PIN rw0_rd_out[83]
    DIRECTION OUTPUT ;
    USE SIGNAL ;
    SHAPE ABUTMENT ;
    PORT
      LAYER metal2 ;
      RECT 64.375 307.790 64.445 308.000 ;
    END
  END rw0_rd_out[83]
  PIN rw0_rd_out[84]
    DIRECTION OUTPUT ;
    USE SIGNAL ;
    SHAPE ABUTMENT ;
    PORT
      LAYER metal2 ;
      RECT 66.085 307.790 66.155 308.000 ;
    END
  END rw0_rd_out[84]
  PIN rw0_rd_out[85]
    DIRECTION OUTPUT ;
    USE SIGNAL ;
    SHAPE ABUTMENT ;
    PORT
      LAYER metal2 ;
      RECT 67.795 307.790 67.865 308.000 ;
    END
  END rw0_rd_out[85]
  PIN rw0_rd_out[86]
    DIRECTION OUTPUT ;
    USE SIGNAL ;
    SHAPE ABUTMENT ;
    PORT
      LAYER metal2 ;
      RECT 69.505 307.790 69.575 308.000 ;
    END
  END rw0_rd_out[86]
  PIN rw0_rd_out[87]
    DIRECTION OUTPUT ;
    USE SIGNAL ;
    SHAPE ABUTMENT ;
    PORT
      LAYER metal2 ;
      RECT 71.215 307.790 71.285 308.000 ;
    END
  END rw0_rd_out[87]
  PIN rw0_rd_out[88]
    DIRECTION OUTPUT ;
    USE SIGNAL ;
    SHAPE ABUTMENT ;
    PORT
      LAYER metal2 ;
      RECT 72.925 307.790 72.995 308.000 ;
    END
  END rw0_rd_out[88]
  PIN rw0_rd_out[89]
    DIRECTION OUTPUT ;
    USE SIGNAL ;
    SHAPE ABUTMENT ;
    PORT
      LAYER metal2 ;
      RECT 74.635 307.790 74.705 308.000 ;
    END
  END rw0_rd_out[89]
  PIN rw0_rd_out[90]
    DIRECTION OUTPUT ;
    USE SIGNAL ;
    SHAPE ABUTMENT ;
    PORT
      LAYER metal2 ;
      RECT 76.345 307.790 76.415 308.000 ;
    END
  END rw0_rd_out[90]
  PIN rw0_rd_out[91]
    DIRECTION OUTPUT ;
    USE SIGNAL ;
    SHAPE ABUTMENT ;
    PORT
      LAYER metal2 ;
      RECT 78.055 307.790 78.125 308.000 ;
    END
  END rw0_rd_out[91]
  PIN r0_rd_out[0]
    DIRECTION OUTPUT ;
    USE SIGNAL ;
    SHAPE ABUTMENT ;
    PORT
      LAYER metal2 ;
      RECT 105.985 0.000 106.055 0.210 ;
    END
  END r0_rd_out[0]
  PIN r0_rd_out[1]
    DIRECTION OUTPUT ;
    USE SIGNAL ;
    SHAPE ABUTMENT ;
    PORT
      LAYER metal2 ;
      RECT 107.125 0.000 107.195 0.210 ;
    END
  END r0_rd_out[1]
  PIN r0_rd_out[2]
    DIRECTION OUTPUT ;
    USE SIGNAL ;
    SHAPE ABUTMENT ;
    PORT
      LAYER metal2 ;
      RECT 108.265 0.000 108.335 0.210 ;
    END
  END r0_rd_out[2]
  PIN r0_rd_out[3]
    DIRECTION OUTPUT ;
    USE SIGNAL ;
    SHAPE ABUTMENT ;
    PORT
      LAYER metal2 ;
      RECT 109.405 0.000 109.475 0.210 ;
    END
  END r0_rd_out[3]
  PIN r0_rd_out[4]
    DIRECTION OUTPUT ;
    USE SIGNAL ;
    SHAPE ABUTMENT ;
    PORT
      LAYER metal2 ;
      RECT 110.545 0.000 110.615 0.210 ;
    END
  END r0_rd_out[4]
  PIN r0_rd_out[5]
    DIRECTION OUTPUT ;
    USE SIGNAL ;
    SHAPE ABUTMENT ;
    PORT
      LAYER metal2 ;
      RECT 111.685 0.000 111.755 0.210 ;
    END
  END r0_rd_out[5]
  PIN r0_rd_out[6]
    DIRECTION OUTPUT ;
    USE SIGNAL ;
    SHAPE ABUTMENT ;
    PORT
      LAYER metal2 ;
      RECT 112.825 0.000 112.895 0.210 ;
    END
  END r0_rd_out[6]
  PIN r0_rd_out[7]
    DIRECTION OUTPUT ;
    USE SIGNAL ;
    SHAPE ABUTMENT ;
    PORT
      LAYER metal2 ;
      RECT 113.965 0.000 114.035 0.210 ;
    END
  END r0_rd_out[7]
  PIN r0_rd_out[8]
    DIRECTION OUTPUT ;
    USE SIGNAL ;
    SHAPE ABUTMENT ;
    PORT
      LAYER metal2 ;
      RECT 115.105 0.000 115.175 0.210 ;
    END
  END r0_rd_out[8]
  PIN r0_rd_out[9]
    DIRECTION OUTPUT ;
    USE SIGNAL ;
    SHAPE ABUTMENT ;
    PORT
      LAYER metal2 ;
      RECT 116.245 0.000 116.315 0.210 ;
    END
  END r0_rd_out[9]
  PIN r0_rd_out[10]
    DIRECTION OUTPUT ;
    USE SIGNAL ;
    SHAPE ABUTMENT ;
    PORT
      LAYER metal2 ;
      RECT 117.385 0.000 117.455 0.210 ;
    END
  END r0_rd_out[10]
  PIN r0_rd_out[11]
    DIRECTION OUTPUT ;
    USE SIGNAL ;
    SHAPE ABUTMENT ;
    PORT
      LAYER metal2 ;
      RECT 118.525 0.000 118.595 0.210 ;
    END
  END r0_rd_out[11]
  PIN r0_rd_out[12]
    DIRECTION OUTPUT ;
    USE SIGNAL ;
    SHAPE ABUTMENT ;
    PORT
      LAYER metal2 ;
      RECT 119.665 0.000 119.735 0.210 ;
    END
  END r0_rd_out[12]
  PIN r0_rd_out[13]
    DIRECTION OUTPUT ;
    USE SIGNAL ;
    SHAPE ABUTMENT ;
    PORT
      LAYER metal2 ;
      RECT 120.805 0.000 120.875 0.210 ;
    END
  END r0_rd_out[13]
  PIN r0_rd_out[14]
    DIRECTION OUTPUT ;
    USE SIGNAL ;
    SHAPE ABUTMENT ;
    PORT
      LAYER metal2 ;
      RECT 121.945 0.000 122.015 0.210 ;
    END
  END r0_rd_out[14]
  PIN r0_rd_out[15]
    DIRECTION OUTPUT ;
    USE SIGNAL ;
    SHAPE ABUTMENT ;
    PORT
      LAYER metal2 ;
      RECT 123.085 0.000 123.155 0.210 ;
    END
  END r0_rd_out[15]
  PIN r0_rd_out[16]
    DIRECTION OUTPUT ;
    USE SIGNAL ;
    SHAPE ABUTMENT ;
    PORT
      LAYER metal2 ;
      RECT 124.225 0.000 124.295 0.210 ;
    END
  END r0_rd_out[16]
  PIN r0_rd_out[17]
    DIRECTION OUTPUT ;
    USE SIGNAL ;
    SHAPE ABUTMENT ;
    PORT
      LAYER metal2 ;
      RECT 125.365 0.000 125.435 0.210 ;
    END
  END r0_rd_out[17]
  PIN r0_rd_out[18]
    DIRECTION OUTPUT ;
    USE SIGNAL ;
    SHAPE ABUTMENT ;
    PORT
      LAYER metal2 ;
      RECT 126.505 0.000 126.575 0.210 ;
    END
  END r0_rd_out[18]
  PIN r0_rd_out[19]
    DIRECTION OUTPUT ;
    USE SIGNAL ;
    SHAPE ABUTMENT ;
    PORT
      LAYER metal2 ;
      RECT 127.645 0.000 127.715 0.210 ;
    END
  END r0_rd_out[19]
  PIN r0_rd_out[20]
    DIRECTION OUTPUT ;
    USE SIGNAL ;
    SHAPE ABUTMENT ;
    PORT
      LAYER metal2 ;
      RECT 128.785 0.000 128.855 0.210 ;
    END
  END r0_rd_out[20]
  PIN r0_rd_out[21]
    DIRECTION OUTPUT ;
    USE SIGNAL ;
    SHAPE ABUTMENT ;
    PORT
      LAYER metal2 ;
      RECT 129.925 0.000 129.995 0.210 ;
    END
  END r0_rd_out[21]
  PIN r0_rd_out[22]
    DIRECTION OUTPUT ;
    USE SIGNAL ;
    SHAPE ABUTMENT ;
    PORT
      LAYER metal2 ;
      RECT 131.065 0.000 131.135 0.210 ;
    END
  END r0_rd_out[22]
  PIN r0_rd_out[23]
    DIRECTION OUTPUT ;
    USE SIGNAL ;
    SHAPE ABUTMENT ;
    PORT
      LAYER metal2 ;
      RECT 132.205 0.000 132.275 0.210 ;
    END
  END r0_rd_out[23]
  PIN r0_rd_out[24]
    DIRECTION OUTPUT ;
    USE SIGNAL ;
    SHAPE ABUTMENT ;
    PORT
      LAYER metal2 ;
      RECT 133.345 0.000 133.415 0.210 ;
    END
  END r0_rd_out[24]
  PIN r0_rd_out[25]
    DIRECTION OUTPUT ;
    USE SIGNAL ;
    SHAPE ABUTMENT ;
    PORT
      LAYER metal2 ;
      RECT 134.485 0.000 134.555 0.210 ;
    END
  END r0_rd_out[25]
  PIN r0_rd_out[26]
    DIRECTION OUTPUT ;
    USE SIGNAL ;
    SHAPE ABUTMENT ;
    PORT
      LAYER metal2 ;
      RECT 135.625 0.000 135.695 0.210 ;
    END
  END r0_rd_out[26]
  PIN r0_rd_out[27]
    DIRECTION OUTPUT ;
    USE SIGNAL ;
    SHAPE ABUTMENT ;
    PORT
      LAYER metal2 ;
      RECT 136.765 0.000 136.835 0.210 ;
    END
  END r0_rd_out[27]
  PIN r0_rd_out[28]
    DIRECTION OUTPUT ;
    USE SIGNAL ;
    SHAPE ABUTMENT ;
    PORT
      LAYER metal2 ;
      RECT 137.905 0.000 137.975 0.210 ;
    END
  END r0_rd_out[28]
  PIN r0_rd_out[29]
    DIRECTION OUTPUT ;
    USE SIGNAL ;
    SHAPE ABUTMENT ;
    PORT
      LAYER metal2 ;
      RECT 139.045 0.000 139.115 0.210 ;
    END
  END r0_rd_out[29]
  PIN r0_rd_out[30]
    DIRECTION OUTPUT ;
    USE SIGNAL ;
    SHAPE ABUTMENT ;
    PORT
      LAYER metal2 ;
      RECT 140.185 0.000 140.255 0.210 ;
    END
  END r0_rd_out[30]
  PIN r0_rd_out[31]
    DIRECTION OUTPUT ;
    USE SIGNAL ;
    SHAPE ABUTMENT ;
    PORT
      LAYER metal2 ;
      RECT 141.325 0.000 141.395 0.210 ;
    END
  END r0_rd_out[31]
  PIN r0_rd_out[32]
    DIRECTION OUTPUT ;
    USE SIGNAL ;
    SHAPE ABUTMENT ;
    PORT
      LAYER metal2 ;
      RECT 142.465 0.000 142.535 0.210 ;
    END
  END r0_rd_out[32]
  PIN r0_rd_out[33]
    DIRECTION OUTPUT ;
    USE SIGNAL ;
    SHAPE ABUTMENT ;
    PORT
      LAYER metal2 ;
      RECT 143.605 0.000 143.675 0.210 ;
    END
  END r0_rd_out[33]
  PIN r0_rd_out[34]
    DIRECTION OUTPUT ;
    USE SIGNAL ;
    SHAPE ABUTMENT ;
    PORT
      LAYER metal2 ;
      RECT 144.745 0.000 144.815 0.210 ;
    END
  END r0_rd_out[34]
  PIN r0_rd_out[35]
    DIRECTION OUTPUT ;
    USE SIGNAL ;
    SHAPE ABUTMENT ;
    PORT
      LAYER metal2 ;
      RECT 145.885 0.000 145.955 0.210 ;
    END
  END r0_rd_out[35]
  PIN r0_rd_out[36]
    DIRECTION OUTPUT ;
    USE SIGNAL ;
    SHAPE ABUTMENT ;
    PORT
      LAYER metal2 ;
      RECT 147.025 0.000 147.095 0.210 ;
    END
  END r0_rd_out[36]
  PIN r0_rd_out[37]
    DIRECTION OUTPUT ;
    USE SIGNAL ;
    SHAPE ABUTMENT ;
    PORT
      LAYER metal2 ;
      RECT 148.165 0.000 148.235 0.210 ;
    END
  END r0_rd_out[37]
  PIN r0_rd_out[38]
    DIRECTION OUTPUT ;
    USE SIGNAL ;
    SHAPE ABUTMENT ;
    PORT
      LAYER metal2 ;
      RECT 149.305 0.000 149.375 0.210 ;
    END
  END r0_rd_out[38]
  PIN r0_rd_out[39]
    DIRECTION OUTPUT ;
    USE SIGNAL ;
    SHAPE ABUTMENT ;
    PORT
      LAYER metal2 ;
      RECT 150.445 0.000 150.515 0.210 ;
    END
  END r0_rd_out[39]
  PIN r0_rd_out[40]
    DIRECTION OUTPUT ;
    USE SIGNAL ;
    SHAPE ABUTMENT ;
    PORT
      LAYER metal2 ;
      RECT 151.585 0.000 151.655 0.210 ;
    END
  END r0_rd_out[40]
  PIN r0_rd_out[41]
    DIRECTION OUTPUT ;
    USE SIGNAL ;
    SHAPE ABUTMENT ;
    PORT
      LAYER metal2 ;
      RECT 152.725 0.000 152.795 0.210 ;
    END
  END r0_rd_out[41]
  PIN r0_rd_out[42]
    DIRECTION OUTPUT ;
    USE SIGNAL ;
    SHAPE ABUTMENT ;
    PORT
      LAYER metal2 ;
      RECT 153.865 0.000 153.935 0.210 ;
    END
  END r0_rd_out[42]
  PIN r0_rd_out[43]
    DIRECTION OUTPUT ;
    USE SIGNAL ;
    SHAPE ABUTMENT ;
    PORT
      LAYER metal2 ;
      RECT 155.005 0.000 155.075 0.210 ;
    END
  END r0_rd_out[43]
  PIN r0_rd_out[44]
    DIRECTION OUTPUT ;
    USE SIGNAL ;
    SHAPE ABUTMENT ;
    PORT
      LAYER metal2 ;
      RECT 156.145 0.000 156.215 0.210 ;
    END
  END r0_rd_out[44]
  PIN r0_rd_out[45]
    DIRECTION OUTPUT ;
    USE SIGNAL ;
    SHAPE ABUTMENT ;
    PORT
      LAYER metal2 ;
      RECT 157.285 0.000 157.355 0.210 ;
    END
  END r0_rd_out[45]
  PIN r0_rd_out[46]
    DIRECTION OUTPUT ;
    USE SIGNAL ;
    SHAPE ABUTMENT ;
    PORT
      LAYER metal2 ;
      RECT 79.765 307.790 79.835 308.000 ;
    END
  END r0_rd_out[46]
  PIN r0_rd_out[47]
    DIRECTION OUTPUT ;
    USE SIGNAL ;
    SHAPE ABUTMENT ;
    PORT
      LAYER metal2 ;
      RECT 81.475 307.790 81.545 308.000 ;
    END
  END r0_rd_out[47]
  PIN r0_rd_out[48]
    DIRECTION OUTPUT ;
    USE SIGNAL ;
    SHAPE ABUTMENT ;
    PORT
      LAYER metal2 ;
      RECT 83.185 307.790 83.255 308.000 ;
    END
  END r0_rd_out[48]
  PIN r0_rd_out[49]
    DIRECTION OUTPUT ;
    USE SIGNAL ;
    SHAPE ABUTMENT ;
    PORT
      LAYER metal2 ;
      RECT 84.895 307.790 84.965 308.000 ;
    END
  END r0_rd_out[49]
  PIN r0_rd_out[50]
    DIRECTION OUTPUT ;
    USE SIGNAL ;
    SHAPE ABUTMENT ;
    PORT
      LAYER metal2 ;
      RECT 86.605 307.790 86.675 308.000 ;
    END
  END r0_rd_out[50]
  PIN r0_rd_out[51]
    DIRECTION OUTPUT ;
    USE SIGNAL ;
    SHAPE ABUTMENT ;
    PORT
      LAYER metal2 ;
      RECT 88.315 307.790 88.385 308.000 ;
    END
  END r0_rd_out[51]
  PIN r0_rd_out[52]
    DIRECTION OUTPUT ;
    USE SIGNAL ;
    SHAPE ABUTMENT ;
    PORT
      LAYER metal2 ;
      RECT 90.025 307.790 90.095 308.000 ;
    END
  END r0_rd_out[52]
  PIN r0_rd_out[53]
    DIRECTION OUTPUT ;
    USE SIGNAL ;
    SHAPE ABUTMENT ;
    PORT
      LAYER metal2 ;
      RECT 91.735 307.790 91.805 308.000 ;
    END
  END r0_rd_out[53]
  PIN r0_rd_out[54]
    DIRECTION OUTPUT ;
    USE SIGNAL ;
    SHAPE ABUTMENT ;
    PORT
      LAYER metal2 ;
      RECT 93.445 307.790 93.515 308.000 ;
    END
  END r0_rd_out[54]
  PIN r0_rd_out[55]
    DIRECTION OUTPUT ;
    USE SIGNAL ;
    SHAPE ABUTMENT ;
    PORT
      LAYER metal2 ;
      RECT 95.155 307.790 95.225 308.000 ;
    END
  END r0_rd_out[55]
  PIN r0_rd_out[56]
    DIRECTION OUTPUT ;
    USE SIGNAL ;
    SHAPE ABUTMENT ;
    PORT
      LAYER metal2 ;
      RECT 96.865 307.790 96.935 308.000 ;
    END
  END r0_rd_out[56]
  PIN r0_rd_out[57]
    DIRECTION OUTPUT ;
    USE SIGNAL ;
    SHAPE ABUTMENT ;
    PORT
      LAYER metal2 ;
      RECT 98.575 307.790 98.645 308.000 ;
    END
  END r0_rd_out[57]
  PIN r0_rd_out[58]
    DIRECTION OUTPUT ;
    USE SIGNAL ;
    SHAPE ABUTMENT ;
    PORT
      LAYER metal2 ;
      RECT 100.285 307.790 100.355 308.000 ;
    END
  END r0_rd_out[58]
  PIN r0_rd_out[59]
    DIRECTION OUTPUT ;
    USE SIGNAL ;
    SHAPE ABUTMENT ;
    PORT
      LAYER metal2 ;
      RECT 101.995 307.790 102.065 308.000 ;
    END
  END r0_rd_out[59]
  PIN r0_rd_out[60]
    DIRECTION OUTPUT ;
    USE SIGNAL ;
    SHAPE ABUTMENT ;
    PORT
      LAYER metal2 ;
      RECT 103.705 307.790 103.775 308.000 ;
    END
  END r0_rd_out[60]
  PIN r0_rd_out[61]
    DIRECTION OUTPUT ;
    USE SIGNAL ;
    SHAPE ABUTMENT ;
    PORT
      LAYER metal2 ;
      RECT 105.415 307.790 105.485 308.000 ;
    END
  END r0_rd_out[61]
  PIN r0_rd_out[62]
    DIRECTION OUTPUT ;
    USE SIGNAL ;
    SHAPE ABUTMENT ;
    PORT
      LAYER metal2 ;
      RECT 107.125 307.790 107.195 308.000 ;
    END
  END r0_rd_out[62]
  PIN r0_rd_out[63]
    DIRECTION OUTPUT ;
    USE SIGNAL ;
    SHAPE ABUTMENT ;
    PORT
      LAYER metal2 ;
      RECT 108.835 307.790 108.905 308.000 ;
    END
  END r0_rd_out[63]
  PIN r0_rd_out[64]
    DIRECTION OUTPUT ;
    USE SIGNAL ;
    SHAPE ABUTMENT ;
    PORT
      LAYER metal2 ;
      RECT 110.545 307.790 110.615 308.000 ;
    END
  END r0_rd_out[64]
  PIN r0_rd_out[65]
    DIRECTION OUTPUT ;
    USE SIGNAL ;
    SHAPE ABUTMENT ;
    PORT
      LAYER metal2 ;
      RECT 112.255 307.790 112.325 308.000 ;
    END
  END r0_rd_out[65]
  PIN r0_rd_out[66]
    DIRECTION OUTPUT ;
    USE SIGNAL ;
    SHAPE ABUTMENT ;
    PORT
      LAYER metal2 ;
      RECT 113.965 307.790 114.035 308.000 ;
    END
  END r0_rd_out[66]
  PIN r0_rd_out[67]
    DIRECTION OUTPUT ;
    USE SIGNAL ;
    SHAPE ABUTMENT ;
    PORT
      LAYER metal2 ;
      RECT 115.675 307.790 115.745 308.000 ;
    END
  END r0_rd_out[67]
  PIN r0_rd_out[68]
    DIRECTION OUTPUT ;
    USE SIGNAL ;
    SHAPE ABUTMENT ;
    PORT
      LAYER metal2 ;
      RECT 117.385 307.790 117.455 308.000 ;
    END
  END r0_rd_out[68]
  PIN r0_rd_out[69]
    DIRECTION OUTPUT ;
    USE SIGNAL ;
    SHAPE ABUTMENT ;
    PORT
      LAYER metal2 ;
      RECT 119.095 307.790 119.165 308.000 ;
    END
  END r0_rd_out[69]
  PIN r0_rd_out[70]
    DIRECTION OUTPUT ;
    USE SIGNAL ;
    SHAPE ABUTMENT ;
    PORT
      LAYER metal2 ;
      RECT 120.805 307.790 120.875 308.000 ;
    END
  END r0_rd_out[70]
  PIN r0_rd_out[71]
    DIRECTION OUTPUT ;
    USE SIGNAL ;
    SHAPE ABUTMENT ;
    PORT
      LAYER metal2 ;
      RECT 122.515 307.790 122.585 308.000 ;
    END
  END r0_rd_out[71]
  PIN r0_rd_out[72]
    DIRECTION OUTPUT ;
    USE SIGNAL ;
    SHAPE ABUTMENT ;
    PORT
      LAYER metal2 ;
      RECT 124.225 307.790 124.295 308.000 ;
    END
  END r0_rd_out[72]
  PIN r0_rd_out[73]
    DIRECTION OUTPUT ;
    USE SIGNAL ;
    SHAPE ABUTMENT ;
    PORT
      LAYER metal2 ;
      RECT 125.935 307.790 126.005 308.000 ;
    END
  END r0_rd_out[73]
  PIN r0_rd_out[74]
    DIRECTION OUTPUT ;
    USE SIGNAL ;
    SHAPE ABUTMENT ;
    PORT
      LAYER metal2 ;
      RECT 127.645 307.790 127.715 308.000 ;
    END
  END r0_rd_out[74]
  PIN r0_rd_out[75]
    DIRECTION OUTPUT ;
    USE SIGNAL ;
    SHAPE ABUTMENT ;
    PORT
      LAYER metal2 ;
      RECT 129.355 307.790 129.425 308.000 ;
    END
  END r0_rd_out[75]
  PIN r0_rd_out[76]
    DIRECTION OUTPUT ;
    USE SIGNAL ;
    SHAPE ABUTMENT ;
    PORT
      LAYER metal2 ;
      RECT 131.065 307.790 131.135 308.000 ;
    END
  END r0_rd_out[76]
  PIN r0_rd_out[77]
    DIRECTION OUTPUT ;
    USE SIGNAL ;
    SHAPE ABUTMENT ;
    PORT
      LAYER metal2 ;
      RECT 132.775 307.790 132.845 308.000 ;
    END
  END r0_rd_out[77]
  PIN r0_rd_out[78]
    DIRECTION OUTPUT ;
    USE SIGNAL ;
    SHAPE ABUTMENT ;
    PORT
      LAYER metal2 ;
      RECT 134.485 307.790 134.555 308.000 ;
    END
  END r0_rd_out[78]
  PIN r0_rd_out[79]
    DIRECTION OUTPUT ;
    USE SIGNAL ;
    SHAPE ABUTMENT ;
    PORT
      LAYER metal2 ;
      RECT 136.195 307.790 136.265 308.000 ;
    END
  END r0_rd_out[79]
  PIN r0_rd_out[80]
    DIRECTION OUTPUT ;
    USE SIGNAL ;
    SHAPE ABUTMENT ;
    PORT
      LAYER metal2 ;
      RECT 137.905 307.790 137.975 308.000 ;
    END
  END r0_rd_out[80]
  PIN r0_rd_out[81]
    DIRECTION OUTPUT ;
    USE SIGNAL ;
    SHAPE ABUTMENT ;
    PORT
      LAYER metal2 ;
      RECT 139.615 307.790 139.685 308.000 ;
    END
  END r0_rd_out[81]
  PIN r0_rd_out[82]
    DIRECTION OUTPUT ;
    USE SIGNAL ;
    SHAPE ABUTMENT ;
    PORT
      LAYER metal2 ;
      RECT 141.325 307.790 141.395 308.000 ;
    END
  END r0_rd_out[82]
  PIN r0_rd_out[83]
    DIRECTION OUTPUT ;
    USE SIGNAL ;
    SHAPE ABUTMENT ;
    PORT
      LAYER metal2 ;
      RECT 143.035 307.790 143.105 308.000 ;
    END
  END r0_rd_out[83]
  PIN r0_rd_out[84]
    DIRECTION OUTPUT ;
    USE SIGNAL ;
    SHAPE ABUTMENT ;
    PORT
      LAYER metal2 ;
      RECT 144.745 307.790 144.815 308.000 ;
    END
  END r0_rd_out[84]
  PIN r0_rd_out[85]
    DIRECTION OUTPUT ;
    USE SIGNAL ;
    SHAPE ABUTMENT ;
    PORT
      LAYER metal2 ;
      RECT 146.455 307.790 146.525 308.000 ;
    END
  END r0_rd_out[85]
  PIN r0_rd_out[86]
    DIRECTION OUTPUT ;
    USE SIGNAL ;
    SHAPE ABUTMENT ;
    PORT
      LAYER metal2 ;
      RECT 148.165 307.790 148.235 308.000 ;
    END
  END r0_rd_out[86]
  PIN r0_rd_out[87]
    DIRECTION OUTPUT ;
    USE SIGNAL ;
    SHAPE ABUTMENT ;
    PORT
      LAYER metal2 ;
      RECT 149.875 307.790 149.945 308.000 ;
    END
  END r0_rd_out[87]
  PIN r0_rd_out[88]
    DIRECTION OUTPUT ;
    USE SIGNAL ;
    SHAPE ABUTMENT ;
    PORT
      LAYER metal2 ;
      RECT 151.585 307.790 151.655 308.000 ;
    END
  END r0_rd_out[88]
  PIN r0_rd_out[89]
    DIRECTION OUTPUT ;
    USE SIGNAL ;
    SHAPE ABUTMENT ;
    PORT
      LAYER metal2 ;
      RECT 153.295 307.790 153.365 308.000 ;
    END
  END r0_rd_out[89]
  PIN r0_rd_out[90]
    DIRECTION OUTPUT ;
    USE SIGNAL ;
    SHAPE ABUTMENT ;
    PORT
      LAYER metal2 ;
      RECT 155.005 307.790 155.075 308.000 ;
    END
  END r0_rd_out[90]
  PIN r0_rd_out[91]
    DIRECTION OUTPUT ;
    USE SIGNAL ;
    SHAPE ABUTMENT ;
    PORT
      LAYER metal2 ;
      RECT 156.715 307.790 156.785 308.000 ;
    END
  END r0_rd_out[91]
  PIN rw0_addr_in[0]
    DIRECTION INPUT ;
    USE SIGNAL ;
    SHAPE ABUTMENT ;
    PORT
      LAYER metal3 ;
      RECT 0.000 226.205 0.210 226.275 ;
    END
  END rw0_addr_in[0]
  PIN rw0_addr_in[1]
    DIRECTION INPUT ;
    USE SIGNAL ;
    SHAPE ABUTMENT ;
    PORT
      LAYER metal3 ;
      RECT 0.000 236.005 0.210 236.075 ;
    END
  END rw0_addr_in[1]
  PIN rw0_addr_in[2]
    DIRECTION INPUT ;
    USE SIGNAL ;
    SHAPE ABUTMENT ;
    PORT
      LAYER metal3 ;
      RECT 0.000 245.805 0.210 245.875 ;
    END
  END rw0_addr_in[2]
  PIN rw0_addr_in[3]
    DIRECTION INPUT ;
    USE SIGNAL ;
    SHAPE ABUTMENT ;
    PORT
      LAYER metal3 ;
      RECT 0.000 255.605 0.210 255.675 ;
    END
  END rw0_addr_in[3]
  PIN rw0_addr_in[4]
    DIRECTION INPUT ;
    USE SIGNAL ;
    SHAPE ABUTMENT ;
    PORT
      LAYER metal3 ;
      RECT 169.840 226.205 170.050 226.275 ;
    END
  END rw0_addr_in[4]
  PIN rw0_addr_in[5]
    DIRECTION INPUT ;
    USE SIGNAL ;
    SHAPE ABUTMENT ;
    PORT
      LAYER metal3 ;
      RECT 169.840 236.005 170.050 236.075 ;
    END
  END rw0_addr_in[5]
  PIN rw0_addr_in[6]
    DIRECTION INPUT ;
    USE SIGNAL ;
    SHAPE ABUTMENT ;
    PORT
      LAYER metal3 ;
      RECT 169.840 245.805 170.050 245.875 ;
    END
  END rw0_addr_in[6]
  PIN rw0_addr_in[7]
    DIRECTION INPUT ;
    USE SIGNAL ;
    SHAPE ABUTMENT ;
    PORT
      LAYER metal3 ;
      RECT 169.840 255.605 170.050 255.675 ;
    END
  END rw0_addr_in[7]
  PIN r0_addr_in[0]
    DIRECTION INPUT ;
    USE SIGNAL ;
    SHAPE ABUTMENT ;
    PORT
      LAYER metal3 ;
      RECT 0.000 265.405 0.210 265.475 ;
    END
  END r0_addr_in[0]
  PIN r0_addr_in[1]
    DIRECTION INPUT ;
    USE SIGNAL ;
    SHAPE ABUTMENT ;
    PORT
      LAYER metal3 ;
      RECT 0.000 275.205 0.210 275.275 ;
    END
  END r0_addr_in[1]
  PIN r0_addr_in[2]
    DIRECTION INPUT ;
    USE SIGNAL ;
    SHAPE ABUTMENT ;
    PORT
      LAYER metal3 ;
      RECT 0.000 285.005 0.210 285.075 ;
    END
  END r0_addr_in[2]
  PIN r0_addr_in[3]
    DIRECTION INPUT ;
    USE SIGNAL ;
    SHAPE ABUTMENT ;
    PORT
      LAYER metal3 ;
      RECT 0.000 294.805 0.210 294.875 ;
    END
  END r0_addr_in[3]
  PIN r0_addr_in[4]
    DIRECTION INPUT ;
    USE SIGNAL ;
    SHAPE ABUTMENT ;
    PORT
      LAYER metal3 ;
      RECT 169.840 265.405 170.050 265.475 ;
    END
  END r0_addr_in[4]
  PIN r0_addr_in[5]
    DIRECTION INPUT ;
    USE SIGNAL ;
    SHAPE ABUTMENT ;
    PORT
      LAYER metal3 ;
      RECT 169.840 275.205 170.050 275.275 ;
    END
  END r0_addr_in[5]
  PIN r0_addr_in[6]
    DIRECTION INPUT ;
    USE SIGNAL ;
    SHAPE ABUTMENT ;
    PORT
      LAYER metal3 ;
      RECT 169.840 285.005 170.050 285.075 ;
    END
  END r0_addr_in[6]
  PIN r0_addr_in[7]
    DIRECTION INPUT ;
    USE SIGNAL ;
    SHAPE ABUTMENT ;
    PORT
      LAYER metal3 ;
      RECT 169.840 294.805 170.050 294.875 ;
    END
  END r0_addr_in[7]
  PIN rw0_we_in
    DIRECTION INPUT ;
    USE SIGNAL ;
    SHAPE ABUTMENT ;
    PORT
      LAYER metal2 ;
      RECT 158.425 307.790 158.495 308.000 ;
    END
  END rw0_we_in
  PIN rw0_ce_in
    DIRECTION INPUT ;
    USE SIGNAL ;
    SHAPE ABUTMENT ;
    PORT
      LAYER metal2 ;
      RECT 160.135 307.790 160.205 308.000 ;
    END
  END rw0_ce_in
  PIN rw0_clk
    DIRECTION INPUT ;
    USE SIGNAL ;
    SHAPE ABUTMENT ;
    PORT
      LAYER metal2 ;
      RECT 161.845 307.790 161.915 308.000 ;
    END
  END rw0_clk
  PIN r0_ce_in
    DIRECTION INPUT ;
    USE SIGNAL ;
    SHAPE ABUTMENT ;
    PORT
      LAYER metal2 ;
      RECT 163.555 307.790 163.625 308.000 ;
    END
  END r0_ce_in
  PIN r0_clk
    DIRECTION INPUT ;
    USE SIGNAL ;
    SHAPE ABUTMENT ;
    PORT
      LAYER metal2 ;
      RECT 165.265 307.790 165.335 308.000 ;
    END
  END r0_clk
  PIN VSS
    DIRECTION INOUT ;
    USE GROUND ;
    PORT
      LAYER metal4 ;
      RECT 1.000 0.840 1.280 307.160 ;
      RECT 3.240 0.840 3.520 307.160 ;
      RECT 5.480 0.840 5.760 307.160 ;
      RECT 7.720 0.840 8.000 307.160 ;
      RECT 9.960 0.840 10.240 307.160 ;
      RECT 12.200 0.840 12.480 307.160 ;
      RECT 14.440 0.840 14.720 307.160 ;
      RECT 16.680 0.840 16.960 307.160 ;
      RECT 18.920 0.840 19.200 307.160 ;
      RECT 21.160 0.840 21.440 307.160 ;
      RECT 23.400 0.840 23.680 307.160 ;
      RECT 25.640 0.840 25.920 307.160 ;
      RECT 27.880 0.840 28.160 307.160 ;
      RECT 30.120 0.840 30.400 307.160 ;
      RECT 32.360 0.840 32.640 307.160 ;
      RECT 34.600 0.840 34.880 307.160 ;
      RECT 36.840 0.840 37.120 307.160 ;
      RECT 39.080 0.840 39.360 307.160 ;
      RECT 41.320 0.840 41.600 307.160 ;
      RECT 43.560 0.840 43.840 307.160 ;
      RECT 45.800 0.840 46.080 307.160 ;
      RECT 48.040 0.840 48.320 307.160 ;
      RECT 50.280 0.840 50.560 307.160 ;
      RECT 52.520 0.840 52.800 307.160 ;
      RECT 54.760 0.840 55.040 307.160 ;
      RECT 57.000 0.840 57.280 307.160 ;
      RECT 59.240 0.840 59.520 307.160 ;
      RECT 61.480 0.840 61.760 307.160 ;
      RECT 63.720 0.840 64.000 307.160 ;
      RECT 65.960 0.840 66.240 307.160 ;
      RECT 68.200 0.840 68.480 307.160 ;
      RECT 70.440 0.840 70.720 307.160 ;
      RECT 72.680 0.840 72.960 307.160 ;
      RECT 74.920 0.840 75.200 307.160 ;
      RECT 77.160 0.840 77.440 307.160 ;
      RECT 79.400 0.840 79.680 307.160 ;
      RECT 81.640 0.840 81.920 307.160 ;
      RECT 83.880 0.840 84.160 307.160 ;
      RECT 86.120 0.840 86.400 307.160 ;
      RECT 88.360 0.840 88.640 307.160 ;
      RECT 90.600 0.840 90.880 307.160 ;
      RECT 92.840 0.840 93.120 307.160 ;
      RECT 95.080 0.840 95.360 307.160 ;
      RECT 97.320 0.840 97.600 307.160 ;
      RECT 99.560 0.840 99.840 307.160 ;
      RECT 101.800 0.840 102.080 307.160 ;
      RECT 104.040 0.840 104.320 307.160 ;
      RECT 106.280 0.840 106.560 307.160 ;
      RECT 108.520 0.840 108.800 307.160 ;
      RECT 110.760 0.840 111.040 307.160 ;
      RECT 113.000 0.840 113.280 307.160 ;
      RECT 115.240 0.840 115.520 307.160 ;
      RECT 117.480 0.840 117.760 307.160 ;
      RECT 119.720 0.840 120.000 307.160 ;
      RECT 121.960 0.840 122.240 307.160 ;
      RECT 124.200 0.840 124.480 307.160 ;
      RECT 126.440 0.840 126.720 307.160 ;
      RECT 128.680 0.840 128.960 307.160 ;
      RECT 130.920 0.840 131.200 307.160 ;
      RECT 133.160 0.840 133.440 307.160 ;
      RECT 135.400 0.840 135.680 307.160 ;
      RECT 137.640 0.840 137.920 307.160 ;
      RECT 139.880 0.840 140.160 307.160 ;
      RECT 142.120 0.840 142.400 307.160 ;
      RECT 144.360 0.840 144.640 307.160 ;
      RECT 146.600 0.840 146.880 307.160 ;
      RECT 148.840 0.840 149.120 307.160 ;
      RECT 151.080 0.840 151.360 307.160 ;
      RECT 153.320 0.840 153.600 307.160 ;
      RECT 155.560 0.840 155.840 307.160 ;
      RECT 157.800 0.840 158.080 307.160 ;
      RECT 160.040 0.840 160.320 307.160 ;
      RECT 162.280 0.840 162.560 307.160 ;
      RECT 164.520 0.840 164.800 307.160 ;
      RECT 166.760 0.840 167.040 307.160 ;
      RECT 169.000 0.840 169.280 307.160 ;
    END
  END VSS
  PIN VDD
    DIRECTION INOUT ;
    USE POWER ;
    PORT
      LAYER metal4 ;
      RECT 2.120 0.840 2.400 307.160 ;
      RECT 4.360 0.840 4.640 307.160 ;
      RECT 6.600 0.840 6.880 307.160 ;
      RECT 8.840 0.840 9.120 307.160 ;
      RECT 11.080 0.840 11.360 307.160 ;
      RECT 13.320 0.840 13.600 307.160 ;
      RECT 15.560 0.840 15.840 307.160 ;
      RECT 17.800 0.840 18.080 307.160 ;
      RECT 20.040 0.840 20.320 307.160 ;
      RECT 22.280 0.840 22.560 307.160 ;
      RECT 24.520 0.840 24.800 307.160 ;
      RECT 26.760 0.840 27.040 307.160 ;
      RECT 29.000 0.840 29.280 307.160 ;
      RECT 31.240 0.840 31.520 307.160 ;
      RECT 33.480 0.840 33.760 307.160 ;
      RECT 35.720 0.840 36.000 307.160 ;
      RECT 37.960 0.840 38.240 307.160 ;
      RECT 40.200 0.840 40.480 307.160 ;
      RECT 42.440 0.840 42.720 307.160 ;
      RECT 44.680 0.840 44.960 307.160 ;
      RECT 46.920 0.840 47.200 307.160 ;
      RECT 49.160 0.840 49.440 307.160 ;
      RECT 51.400 0.840 51.680 307.160 ;
      RECT 53.640 0.840 53.920 307.160 ;
      RECT 55.880 0.840 56.160 307.160 ;
      RECT 58.120 0.840 58.400 307.160 ;
      RECT 60.360 0.840 60.640 307.160 ;
      RECT 62.600 0.840 62.880 307.160 ;
      RECT 64.840 0.840 65.120 307.160 ;
      RECT 67.080 0.840 67.360 307.160 ;
      RECT 69.320 0.840 69.600 307.160 ;
      RECT 71.560 0.840 71.840 307.160 ;
      RECT 73.800 0.840 74.080 307.160 ;
      RECT 76.040 0.840 76.320 307.160 ;
      RECT 78.280 0.840 78.560 307.160 ;
      RECT 80.520 0.840 80.800 307.160 ;
      RECT 82.760 0.840 83.040 307.160 ;
      RECT 85.000 0.840 85.280 307.160 ;
      RECT 87.240 0.840 87.520 307.160 ;
      RECT 89.480 0.840 89.760 307.160 ;
      RECT 91.720 0.840 92.000 307.160 ;
      RECT 93.960 0.840 94.240 307.160 ;
      RECT 96.200 0.840 96.480 307.160 ;
      RECT 98.440 0.840 98.720 307.160 ;
      RECT 100.680 0.840 100.960 307.160 ;
      RECT 102.920 0.840 103.200 307.160 ;
      RECT 105.160 0.840 105.440 307.160 ;
      RECT 107.400 0.840 107.680 307.160 ;
      RECT 109.640 0.840 109.920 307.160 ;
      RECT 111.880 0.840 112.160 307.160 ;
      RECT 114.120 0.840 114.400 307.160 ;
      RECT 116.360 0.840 116.640 307.160 ;
      RECT 118.600 0.840 118.880 307.160 ;
      RECT 120.840 0.840 121.120 307.160 ;
      RECT 123.080 0.840 123.360 307.160 ;
      RECT 125.320 0.840 125.600 307.160 ;
      RECT 127.560 0.840 127.840 307.160 ;
      RECT 129.800 0.840 130.080 307.160 ;
      RECT 132.040 0.840 132.320 307.160 ;
      RECT 134.280 0.840 134.560 307.160 ;
      RECT 136.520 0.840 136.800 307.160 ;
      RECT 138.760 0.840 139.040 307.160 ;
      RECT 141.000 0.840 141.280 307.160 ;
      RECT 143.240 0.840 143.520 307.160 ;
      RECT 145.480 0.840 145.760 307.160 ;
      RECT 147.720 0.840 148.000 307.160 ;
      RECT 149.960 0.840 150.240 307.160 ;
      RECT 152.200 0.840 152.480 307.160 ;
      RECT 154.440 0.840 154.720 307.160 ;
      RECT 156.680 0.840 156.960 307.160 ;
      RECT 158.920 0.840 159.200 307.160 ;
      RECT 161.160 0.840 161.440 307.160 ;
      RECT 163.400 0.840 163.680 307.160 ;
      RECT 165.640 0.840 165.920 307.160 ;
      RECT 167.880 0.840 168.160 307.160 ;
    END
  END VDD
  OBS
    LAYER metal1 ;
    RECT 0 0 170.050 308.000 ;
    LAYER metal2 ;
    RECT 0 0 170.050 308.000 ;
    LAYER metal3 ;
    RECT 0 0 170.050 308.000 ;
    LAYER metal4 ;
    RECT 0 0 170.050 308.000 ;
    LAYER OVERLAP ;
    RECT 0 0 170.050 308.000 ;
  END
END fakeram_1rw1r_92w256d_sram

END LIBRARY
